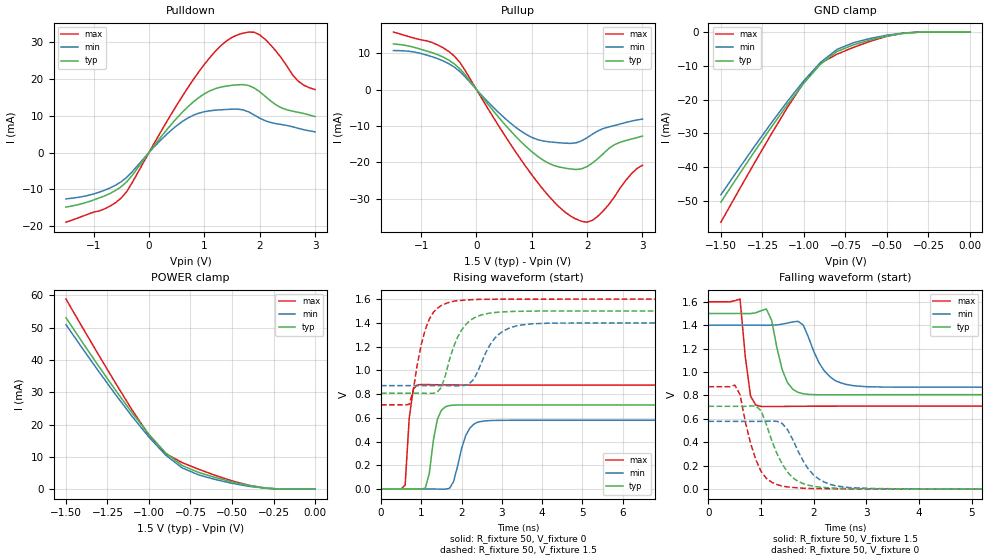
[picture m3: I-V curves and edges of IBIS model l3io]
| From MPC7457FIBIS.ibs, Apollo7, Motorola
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| *   l3io Model   *
[Model]   l3io
Model_type   I/O
Polarity   Non-Inverting
Vinl = 0.53V
Vinh = 0.98V
Vmeas = 0.75V
Cref = 0
Rref = 50
Vref = 0.75V
|   typ   min   max
C_comp   4.844744e-12   3.894058e-12   4.949593e-12
|   typ   min   max
[Voltage range]   1.5V   1.4V   1.6V
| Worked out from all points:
|   slope of the pulldown table from 0 to 0.225 V, typ, clamps not added: 50.9 ohm
|   slope of the pullup table from 0 to 0.225 V, typ, clamps not added: 51.4 ohm
|   GND clamp passes 1 mA (typ) near -0.48 V on its own axis
|   POWER clamp passes 1 mA (typ) near -0.38 V on its own axis
|   falling waveform, R_fixture 50, V_fixture 1.5: 20-80 % time 234ps typ, 370ps min, 131ps max; typ from 1.5 V to 0.807 V
|   rising waveform, R_fixture 50, V_fixture 0: 20-80 % time 185ps typ, 283ps min, 118ps max; typ from 0 V to 0.708 V
|   falling waveform, R_fixture 50, V_fixture 0: 20-80 % time 423ps typ, 456ps min, 330ps max; typ from 0.708 V to 0 V
|   rising waveform, R_fixture 50, V_fixture 1.5: 20-80 % time 464ps typ, 510ps min, 361ps max; typ from 0.807 V to 1.5 V
[Pulldown]
|   Voltage   I(typ)   I(min)   I(max)
-1.5V     -14.86mA   -12.61mA   -18.96mA
-800mV    -11.8mA    -10.26mA   -15.34mA
-500mV    -9.279mA   -7.929mA   -12.35mA
-300mV    -6.153mA   -5.167mA   -8.11mA
600mV     10.93mA    8.436mA    15.27mA
1V        15.98mA    11.12mA    24mA
1.5V      18.31mA    11.81mA    31.36mA
1.8V      18.26mA    11.08mA    32.81mA
2V        16.57mA    9.361mA    32.05mA
2.4V      12.12mA    7.616mA    25.59mA
2.7V      10.95mA    6.591mA    19.39mA
3V        9.787mA    5.654mA    17.17mA
[GND_clamp]
-1.5V     -50.41mA   -48.24mA   -56.36mA
-1.3V     -35.6mA    -34.05mA   -38.99mA
-1.1V     -21.55mA   -20.59mA   -22.4mA
-1V       -15.09mA   -14.4mA    -14.88mA
-900mV    -9.505mA   -8.982mA   -9.26mA
-800mV    -5.731mA   -5.118mA   -6.527mA
-700mV    -3.75mA    -3.13mA    -4.513mA
-600mV    -2.328mA   -1.88mA    -2.72mA
-500mV    -1.181mA   -917uA     -1.23mA
-400mV    -391uA     -287.5uA   -276.3uA
-300mV    0A         0A         0A
0V        0A         0A         0A
[Pullup]
-1.5V     12.53mA    10.71mA    15.8mA
-800mV    10.14mA    9.01mA     12.93mA
-400mV    7.059mA    6.18mA     9.2mA
400mV     -7.609mA   -6.306mA   -9.942mA
900mV     -15.72mA   -12.34mA   -21.34mA
1.3V      -20.23mA   -14.34mA   -29.16mA
1.8V      -21.97mA   -14.65mA   -35.61mA
2V        -21.16mA   -13.23mA   -36.46mA
2.2V      -18.9mA    -11.33mA   -34.73mA
2.5V      -15.11mA   -9.868mA   -29.35mA
2.8V      -13.61mA   -8.672mA   -23.14mA
3V        -12.79mA   -8.128mA   -20.82mA
[POWER_clamp]
-1.5V     53.04mA    50.9mA     58.83mA
-1.3V     37.83mA    36.23mA    41.25mA
-1.1V     23.51mA    22.41mA    24.37mA
-1V       16.95mA    16.1mA     16.69mA
-900mV    11.23mA    10.57mA    11mA
-800mV    7.303mA    6.571mA    8.22mA
-700mV    5.165mA    4.405mA    6.145mA
-600mV    3.596mA    2.979mA    4.258mA
-400mV    1.161mA    894.5uA    1.202mA
-300mV    400.8uA    288.6uA    302.9uA
-200mV    0A         0A         0A
0V        0A         0A         0A
|   typ   min   max
[Ramp]
dV/dt_r   0.42444/1.76894e-10   0.34735/2.68600e-10   0.52504/9.44982e-11
dV/dt_f   0.41587/2.23834e-10   0.31747/3.61693e-10   0.53437/1.09026e-10
[Falling Waveform]
R_fixture = 50
V_fixture = 1.5
V_fixture_min = 1.4
V_fixture_max = 1.6
| time   V(typ)   V(min)   V(max)
0s        1.5V       1.4V       1.6V
600ps     1.5V       1.4V       1.623V
800ps     1.499V     1.4V       793.8mV
1ns       1.524V     1.4V       706.6mV
1.2ns     1.441V     1.4V       705.6mV
1.5ns     910mV      1.418V     706.8mV
1.9ns     809.3mV    1.295V     708.1mV
2.3ns     805.7mV    962.9mV    708.5mV
3ns       806.3mV    875mV      709mV
19.7ns    806.8mV    870.8mV    709.4mV
[Rising Waveform]
R_fixture = 50
V_fixture = 0
V_fixture_min = 0
V_fixture_max = 0
| time   V(typ)   V(min)   V(max)
0s        222.4uV    255.1uV    166.5uV
600ps     471.9uV    466.9uV    35.04mV
700ps     478.2uV    472.2uV    593.4mV
900ps     -47.89uV   451.5uV    876.2mV
1.1ns     7.623mV    428.5uV    880.1mV
1.4ns     587.1mV    -55.82uV   878.2mV
1.7ns     703.2mV    6.071mV    877mV
2.1ns     708mV      447.5mV    876.1mV
2.6ns     708mV      574.3mV    875.6mV
19.7ns    707.6mV    579.2mV    875.2mV
[Falling Waveform]
R_fixture = 50
V_fixture = 0
V_fixture_min = 0
V_fixture_max = 0
| time   V(typ)   V(min)   V(max)
0s        707.6mV    579.2mV    875.2mV
500ps     707.4mV    579.1mV    888.1mV
600ps     707.3mV    578.9mV    806.8mV
700ps     707.4mV    578.9mV    574.5mV
900ps     710.9mV    578.8mV    252.2mV
1.1ns     551.5mV    579.8mV    91.24mV
1.5ns     146.8mV    509.2mV    19.5mV
2ns       24.5mV     119.1mV    5.662mV
2.7ns     5.611mV    13.7mV     2.411mV
19.7ns    236uV      259.9uV    168.5uV
[Rising Waveform]
R_fixture = 50
V_fixture = 1.5
V_fixture_min = 1.4
V_fixture_max = 1.6
| time   V(typ)   V(min)   V(max)
0s        806.8mV    870.8mV    709.3mV
700ps     806.9mV    870.9mV    712.9mV
1.1ns     806.4mV    871mV      1.343V
1.4ns     818mV      871mV      1.523V
1.5ns     857.4mV    870.9mV    1.546V
1.9ns     1.278V     869.4mV    1.587V
2.3ns     1.439V     923.7mV    1.596V
2.9ns     1.489V     1.297V     1.599V
3.7ns     1.498V     1.39V      1.599V
19.7ns    1.5V       1.4V       1.6V
